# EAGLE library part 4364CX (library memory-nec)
MEMORY

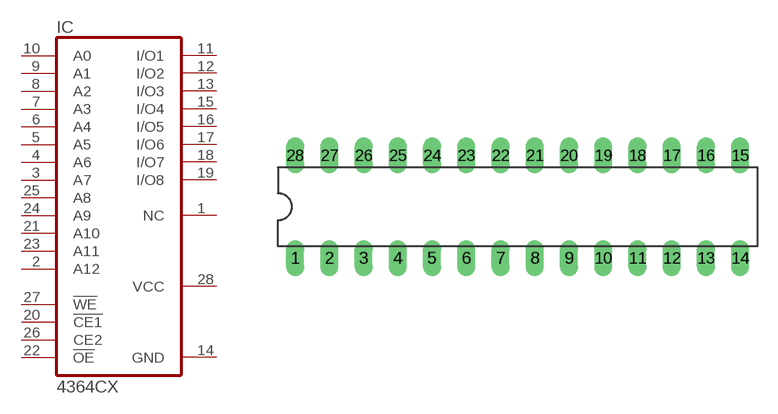
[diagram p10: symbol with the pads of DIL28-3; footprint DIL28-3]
Designator prefix IC

## 4364CX (OC_FARNELL: unknown; OC_NEWARK: unknown)  [DIL28-3]
1  NC  nc
2  A12  in
3  A7  in
4  A6  in
5  A5  in
6  A4  in
7  A3  in
8  A2  in
9  A1  in
10  A0  in
11  I/O1
12  I/O2
13  I/O3
14  GND  pwr
15  I/O4
16  I/O5
17  I/O6
18  I/O7
19  I/O8
20  !CE1  in
21  A10  in
22  !OE  in
23  A11  in
24  A9  in
25  A8  in
26  CE2  in
27  !WE  in
28  VCC  pwr

## Footprint DIL28-3 (pad centres in mm)
Dual In Line Package Small
drill 0.813 long: 1 -16.51,-3.81; 2 -13.97,-3.81; 3 -11.43,-3.81; 4 -8.89,-3.81; 5 -6.35,-3.81; 6 -3.81,-3.81; 7 -1.27,-3.81; 8 1.27,-3.81; 9 3.81,-3.81; 10 6.35,-3.81; 11 8.89,-3.81; 12 11.43,-3.81; 13 13.97,-3.81; 14 16.51,-3.81; 15 16.51,3.81; 16 13.97,3.81; 17 11.43,3.81; 18 8.89,3.81; 19 6.35,3.81; 20 3.81,3.81; 21 1.27,3.81; 22 -1.27,3.81; 23 -3.81,3.81; 24 -6.35,3.81; 25 -8.89,3.81; 26 -11.43,3.81; 27 -13.97,3.81; 28 -16.51,3.81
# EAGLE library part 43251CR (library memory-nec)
MEMORY

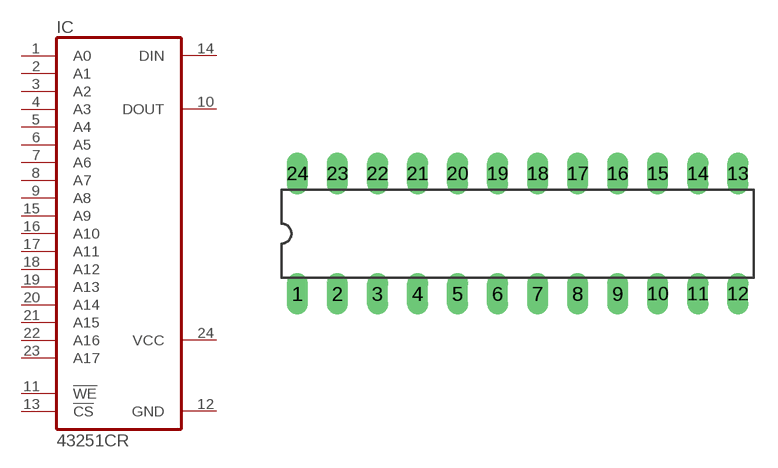
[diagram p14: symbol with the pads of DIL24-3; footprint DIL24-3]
Designator prefix IC

## 43251CR (OC_FARNELL: unknown; OC_NEWARK: unknown)  [DIL24-3]
1  A0  in
2  A1  in
3  A2  in
4  A3  in
5  A4  in
6  A5  in
7  A6  in
8  A7  in
9  A8  in
10  DOUT  hiz
11  !WE  in
12  GND  pwr
13  !CS  in
14  DIN  in
15  A9  in
16  A10  in
17  A11  in
18  A12  in
19  A13  in
20  A14  in
21  A15  in
22  A16  in
23  A17  in
24  VCC  pwr

## Footprint DIL24-3 (pad centres in mm)
Dual In Line Package 0.3 inch
drill 0.813 long: 1 -13.97,-3.81; 2 -11.43,-3.81; 3 -8.89,-3.81; 4 -6.35,-3.81; 5 -3.81,-3.81; 6 -1.27,-3.81; 7 1.27,-3.81; 8 3.81,-3.81; 9 6.35,-3.81; 10 8.89,-3.81; 11 11.43,-3.81; 12 13.97,-3.81; 13 13.97,3.81; 14 11.43,3.81; 15 8.89,3.81; 16 6.35,3.81; 17 3.81,3.81; 18 1.27,3.81; 19 -1.27,3.81; 20 -3.81,3.81; 21 -6.35,3.81; 22 -8.89,3.81; 23 -11.43,3.81; 24 -13.97,3.81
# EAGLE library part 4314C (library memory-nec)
MEMORY

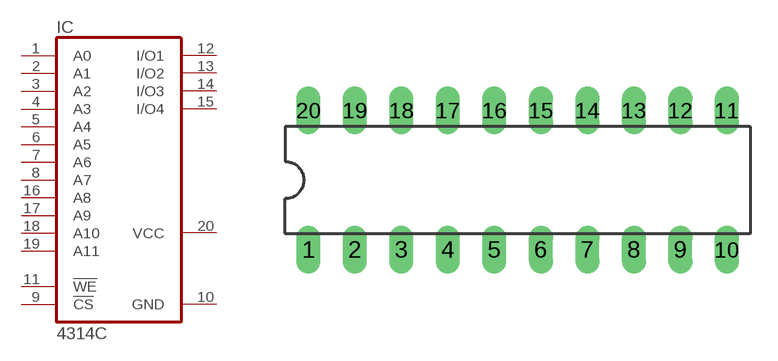
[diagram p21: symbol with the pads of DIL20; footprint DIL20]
Designator prefix IC

## 4314C (OC_FARNELL: unknown; OC_NEWARK: unknown)  [DIL20]
1  A0  in
2  A1  in
3  A2  in
4  A3  in
5  A4  in
6  A5  in
7  A6  in
8  A7  in
9  !CS  in
10  GND  pwr
11  !WE  in
12  I/O1
13  I/O2
14  I/O3
15  I/O4
16  A8  in
17  A9  in
18  A10  in
19  A11  in
20  VCC  pwr

## Footprint DIL20 (pad centres in mm)
Dual In Line Package
drill 0.813 long: 1 -11.43,-3.81; 2 -8.89,-3.81; 3 -6.35,-3.81; 4 -3.81,-3.81; 5 -1.27,-3.81; 6 1.27,-3.81; 7 3.81,-3.81; 8 6.35,-3.81; 9 8.89,-3.81; 10 11.43,-3.81; 11 11.43,3.81; 12 8.89,3.81; 13 6.35,3.81; 14 3.81,3.81; 15 1.27,3.81; 16 -1.27,3.81; 17 -3.81,3.81; 18 -6.35,3.81; 19 -8.89,3.81; 20 -11.43,3.81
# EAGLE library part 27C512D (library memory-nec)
MEMORY

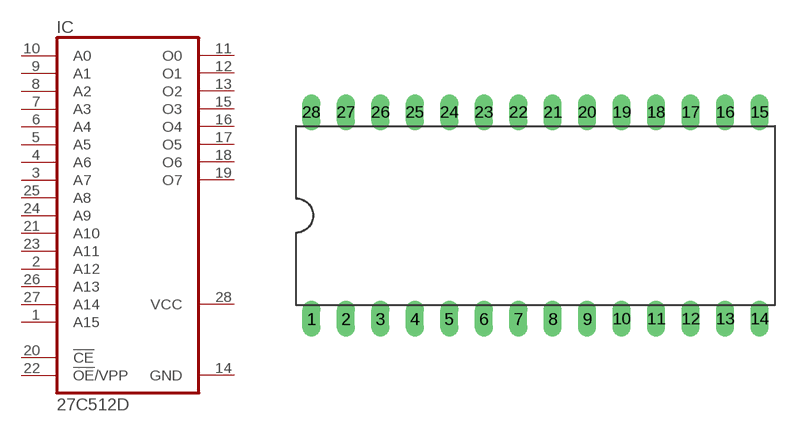
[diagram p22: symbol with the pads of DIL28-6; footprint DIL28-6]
Designator prefix IC

## 27C512D (MPN: M27C512-10F1; OC_FARNELL: 1661676; OC_NEWARK: 56P9224)  [DIL28-6]
1  A15  in
2  A12  in
3  A7  in
4  A6  in
5  A5  in
6  A4  in
7  A3  in
8  A2  in
9  A1  in
10  A0  in
11  O0  hiz
12  O1  hiz
13  O2  hiz
14  GND  pwr
15  O3  hiz
16  O4  hiz
17  O5  hiz
18  O6  hiz
19  O7  hiz
20  !CE  in
21  A10  in
22  !OE!/VPP  in
23  A11  in
24  A9  in
25  A8  in
26  A13  in
27  A14  in
28  VCC  pwr

## Footprint DIL28-6 (pad centres in mm)
Dual In Line Package 0.6 inch
drill 0.813 long: 1 -16.51,-7.62; 2 -13.97,-7.62; 3 -11.43,-7.62; 4 -8.89,-7.62; 5 -6.35,-7.62; 6 -3.81,-7.62; 7 -1.27,-7.62; 8 1.27,-7.62; 9 3.81,-7.62; 10 6.35,-7.62; 11 8.89,-7.62; 12 11.43,-7.62; 13 13.97,-7.62; 14 16.51,-7.62; 15 16.51,7.62; 16 13.97,7.62; 17 11.43,7.62; 18 8.89,7.62; 19 6.35,7.62; 20 3.81,7.62; 21 1.27,7.62; 22 -1.27,7.62; 23 -3.81,7.62; 24 -6.35,7.62; 25 -8.89,7.62; 26 -11.43,7.62; 27 -13.97,7.62; 28 -16.51,7.62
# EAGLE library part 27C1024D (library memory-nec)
MEMORY

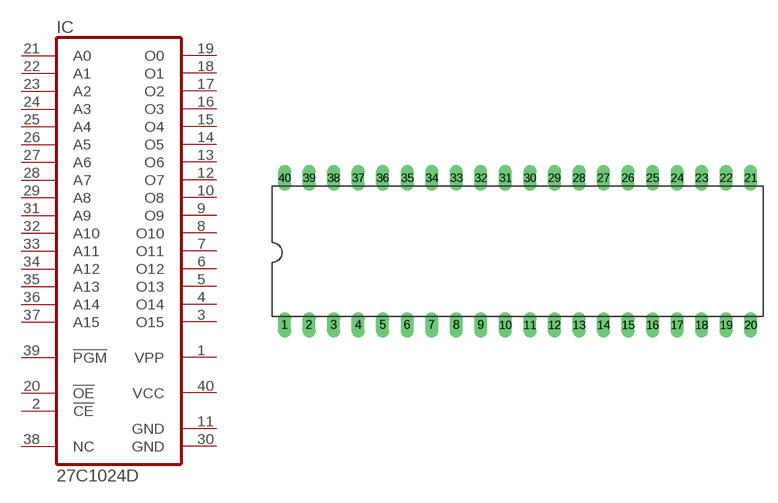
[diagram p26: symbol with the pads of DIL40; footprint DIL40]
Designator prefix IC

## 27C1024D (MPN: M27C1024-70C1; OC_FARNELL: unknown; OC_NEWARK: 37M4699)  [DIL40]
1  VPP  pas
2  !CE  in
3  O15  hiz
4  O14  hiz
5  O13  hiz
6  O12  hiz
7  O11  hiz
8  O10  hiz
9  O9  hiz
10  O8  hiz
11  GND  pwr
12  O7  hiz
13  O6  hiz
14  O5  hiz
15  O4  hiz
16  O3  hiz
17  O2  hiz
18  O1  hiz
19  O0  hiz
20  !OE  in
21  A0  in
22  A1  in
23  A2  in
24  A3  in
25  A4  in
26  A5  in
27  A6  in
28  A7  in
29  A8  in
30  GND  pwr
31  A9  in
32  A10  in
33  A11  in
34  A12  in
35  A13  in
36  A14  in
37  A15  in
38  NC  nc
39  !PGM  in
40  VCC  pwr

## Footprint DIL40 (pad centres in mm)
Dual In Line Package
drill 0.813 long: 1 -24.13,-7.62; 2 -21.59,-7.62; 3 -19.05,-7.62; 4 -16.51,-7.62; 5 -13.97,-7.62; 6 -11.43,-7.62; 7 -8.89,-7.62; 8 -6.35,-7.62; 9 -3.81,-7.62; 10 -1.27,-7.62; 11 1.27,-7.62; 12 3.81,-7.62; 13 6.35,-7.62; 14 8.89,-7.62; 15 11.43,-7.62; 16 13.97,-7.62; 17 16.51,-7.62; 18 19.05,-7.62; 19 21.59,-7.62; 20 24.13,-7.62; 21 24.13,7.62; 22 21.59,7.62; 23 19.05,7.62; 24 16.51,7.62; 25 13.97,7.62; 26 11.43,7.62; 27 8.89,7.62; 28 6.35,7.62; 29 3.81,7.62; 30 1.27,7.62; 31 -1.27,7.62; 32 -3.81,7.62; 33 -6.35,7.62; 34 -8.89,7.62; 35 -11.43,7.62; 36 -13.97,7.62; 37 -16.51,7.62; 38 -19.05,7.62; 39 -21.59,7.62; 40 -24.13,7.62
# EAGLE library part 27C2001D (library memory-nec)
MEMORY

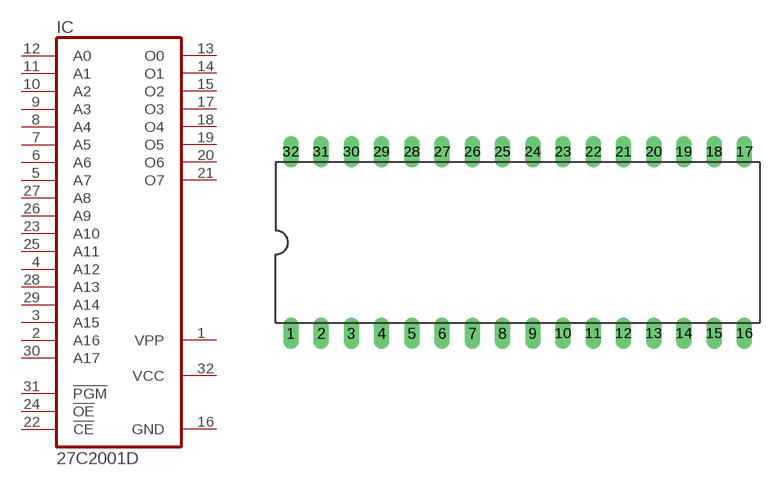
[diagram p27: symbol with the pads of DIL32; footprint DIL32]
Designator prefix IC

## 27C2001D (MPN: M27C2001-10B1; OC_FARNELL: 3338101; OC_NEWARK: 37M4702)  [DIL32]
1  VPP  pas
2  A16  in
3  A15  in
4  A12  in
5  A7  in
6  A6  in
7  A5  in
8  A4  in
9  A3  in
10  A2  in
11  A1  in
12  A0  in
13  O0  hiz
14  O1  hiz
15  O2  hiz
16  GND  pwr
17  O3  hiz
18  O4  hiz
19  O5  hiz
20  O6  hiz
21  O7  hiz
22  !CE  in
23  A10  in
24  !OE  in
25  A11  in
26  A9  in
27  A8  in
28  A13  in
29  A14  in
30  A17  in
31  !PGM  in
32  VCC  pwr

## Footprint DIL32 (pad centres in mm)
Dual In Line Package
drill 0.813 long: 1 -19.05,-7.62; 2 -16.51,-7.62; 3 -13.97,-7.62; 4 -11.43,-7.62; 5 -8.89,-7.62; 6 -6.35,-7.62; 7 -3.81,-7.62; 8 -1.27,-7.62; 9 1.27,-7.62; 10 3.81,-7.62; 11 6.35,-7.62; 12 8.89,-7.62; 13 11.43,-7.62; 14 13.97,-7.62; 15 16.51,-7.62; 16 19.05,-7.62; 17 19.05,7.62; 18 16.51,7.62; 19 13.97,7.62; 20 11.43,7.62; 21 8.89,7.62; 22 6.35,7.62; 23 3.81,7.62; 24 1.27,7.62; 25 -1.27,7.62; 26 -3.81,7.62; 27 -6.35,7.62; 28 -8.89,7.62; 29 -11.43,7.62; 30 -13.97,7.62; 31 -16.51,7.62; 32 -19.05,7.62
